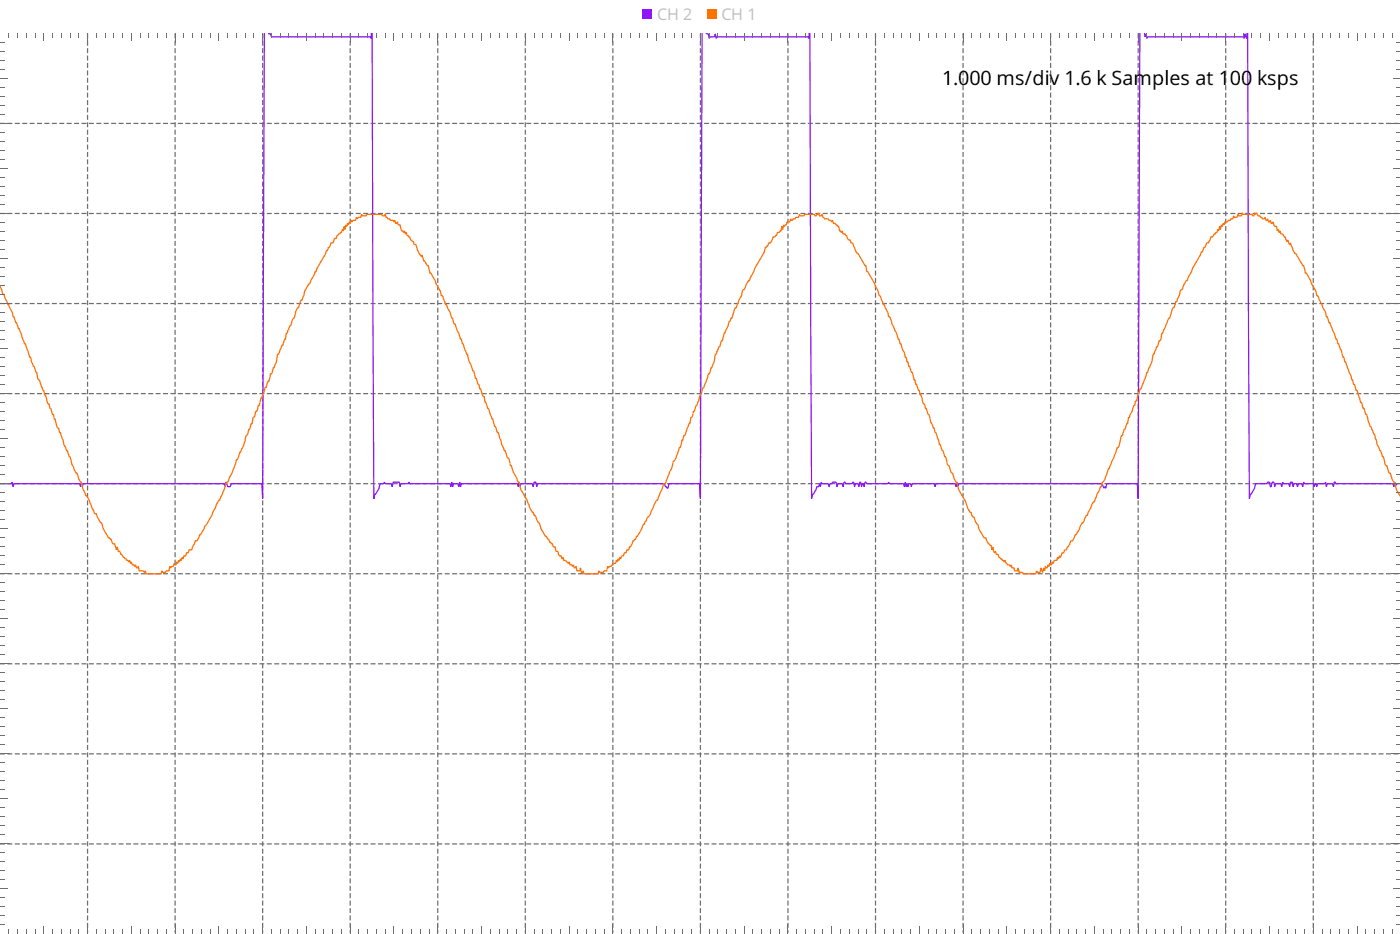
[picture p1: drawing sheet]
<svg xmlns="http://www.w3.org/2000/svg" width="300mm" height="200mm" viewBox="0 0 300 200" stroke-linecap="round" stroke-linejoin="round" font-family="sans-serif">
<defs><g id="words">
<g font-size="4.2">
<text x="201.8" y="18.2">1.000 ms/div 1.6 k Samples at 1</text>
<text x="263.4" y="18.2">00 ksps</text>
</g>
<g font-size="3.4" fill="#bebebe">
<text x="140.8" y="4.2">CH 2</text>
<text x="154.5" y="4.2">CH 1</text>
</g>
</g></defs>
<g fill="none" stroke="#6e6e6f" stroke-width=".26" stroke-dasharray="1.1 .5" stroke-linecap="butt">
<path d="M18.8 7.1v192.7M37.5 7.1v192.7M56.3 7.1v192.7M75 7.1v192.7M93.8 7.1v192.7M112.5 7.1v192.7M131.3 7.1v192.7M150 7.1v192.7M168.8 7.1v192.7M187.5 7.1v192.7M206.3 7.1v192.7M225 7.1v192.7"/>
<path d="M243.8 7.1v192.7M262.5 7.1v192.7M281.3 7.1v192.7M0 26.4h299.8M0 45.7h299.8M0 65h299.8M0 84.3h299.8M0 103.6h299.8M0 122.9h299.8M0 142.2h299.8M0 161.4h299.8M0 180.7h299.8"/>
</g>
<path d="M56.6 7.1l-.3 99.7-.2-3.2h-6.6l-.2 .6h-.5l-.4-.9-.2 .9-.2-.6h-30.2l-.2 .6-.2-.9-.1 .9-.2-.6h-14.1l-.2 .6-.2-.9-.2 .3h-2.4M57.5 7.1l.1 .2h.3l.2 .6h21.2l.2 .3 .1-1.1M79.7 7.1l.4 99.7 .2-1h.1l.8-1.2 .2-1h.7l.2-.3 .2 .3h1.3l.2 .6 .2-.9h1.3l.2 .9 .2-.6h1.5l.2-.3 .2 .3h8.6l.2 .6 .2-.9 .1 .9 .2-.6h1l.2 .6 .1-.9 .2 .9 .2-.6h12l.2 .6 .2-.9 .2 .9 .2-.6h2.4l.2 .6 .2-.9h.4l.2 .9 .1-.6h27.2l.2 .6h.2l.2 .4h.2l.2-1h6.5l.2 3.2 .4-99.7M151.3 7.1v.2h.4l.2 .9 .2-.3h.9l.2-.6 .2 .9 .2-.3h19.5l.2 .3v-1.1M173.5 7.1l.3 99.7 .2-1h.2l.8-1.6h.3l.2-.6 .2 .6 .2-.9 .2 .3h1.3l.2 .6 .2-.6h.3l.2-.3h.8l.2 .9 .2-.6h.9l.2 .6 .2-.9h.2l.1 .3h1.4l.1-.3h.2l.2 .9 .2-.6h.6l.2 .6 .1-.9h.2l.2 .9 .2-.6h.2l.2 .6 .2-.9h.2l.1 .3h4.5l.2-.3 .2 .3h3l.2 .6 .2-.9 .2 .9 .2-.6 .2 .6 .1-.6h.4l.2 .6 .2-.6h4.7l.2 .6 .2-.6h4.1l.2 .6 .2-.9 .2 .9 .1-.6h30.8l.4 1 .2-.4 .1 .4 .2-1h6.6l.2 3.2 .3-99.7M245.1 7.1l.2 .8 .2-.6 .2 .9 .1-.3h20.5l.2 .3 .2-.9 .3 .9 .1-1.1M267.2 7.1l.4 99.7 .2-1h.2l.7-1.2 .2-1h2.4l.2-.3h.4l.2 .9h.2l.2-.9h.3l.2 .9 .2-.6h1.1l.2 .6 .2-.9 .2 .3h1.1l.2 .6 .2-.9h.4l.2 .9 .2-.6h.5l.2 .6 .2-.6h.7l.2 .6 .2-.9 .2 .3h1.9l.2 .6 .2-.6h.1l.2 .6 .2-.6h1.5l.2-.3 .2 .9 .2-.6h1.1l.2 .6 .2-.9h.2l.2 .3h12.1l.2 .6 .2-.9 .2 .9 .2-.6h.7" fill="none" stroke="#9013fe" stroke-width=".26"/>
<path d="M0 61.4l.4 .6 .2 1h.2l.1 .3 .8 1.9h.2l.7 1.7 .2 .9h.2l.4 1.3h.2l.3 1.3h.2l.4 1 .8 2.2h.1l1.7 4.9h.2l.4 1.2h.2l.2 1.3 .2 .4h.1l.8 2.2h.2l.7 2.6 .2 .3h.2l.2 1h.2l.4 1.3h.1l.8 2.5 .2 .4h.2l.2 .9h.1l.8 2.6 .6 1.3h.1l.4 1.3h.2l.4 1.6 .4 .6a1.58 1.58 0 0 0 .7 1.3l.4 1.3 .4 .7h.1l.4 1.6 .6 1.3h.2l.5 .9 1.2 2.9h.3l.2 .7 .8 1.3h.2l.3 1.2 1.2 2 .5 .3 .4 1h.4l.3 1.3 .2-.7 .2 1h.4l.2 .6h.2l.3 .7 1 .6 .2 .3 .2-.3 .1 .7 .2-.4 .2 .7h.4l.2 .3 .2-.3 .2 .6h.1l.2-.3 .2 1h1l.1 .3 .2-.3 .2 .6h3.2l.2-.6 .2 .3h.5l.2-.3h.6l.2-1 .2 .3 .2-.3h.3l.2-.6 .2 .3h.2l.2-.7 .2 .4 .2-.7 .1 .3 .2-.6 .2 .3 .2-.6 .2 .3 .2-.7h.4l.1-.6h.4l.2-.6h.6l.7-2h.2a1.58 1.58 0 0 0 .8-1.3h.1l.8-1.3 .2-.6h.2l1.3-2.2 .9-2.3 .6-1h.2l1.3-3.5 .5-.7 .8-1.6 .7-1.9 .2-1h.2l.2-.3 .4-1.3h.2l.5-1.3 .6-2.2h.2l.2-.3 .2-1h.1l.4-1.3h.2l.2-1.3h.2l.4-1.3h.1l.2-.3 .8-2.6h.2l.7-2.2h.2l.4-1.3h.2l.3-1.6h.2l.2-.4 .2-.9h.2l.4-1 .3-1.9h.2l.2-.3 .6-1.7h.2l.3-1.2h.2l.2-1.3h.2l.6-1.6h.2l.3-1.3 .2-.4h.2l.4-1.6 .4-.6h.1l.4-1.3 .2-.3h.2l.6-2 .9-1.6h.2l1.1-2.5h.2l.2-.7 1.9-3.2 .1-.7h.2l.2-.6h.2l.2-.3 .2-.7h.4l.3-.9h.4l.2-.7 .9-.6 .2-.7 .2 .4 .2-1 .2 .6 .2-.9 .2 .3 .1-.7 .2 .4 .2-.7 .2 .3 .2-.6 .2 .3 .2-.3h.5l.2-.6 .2 .3 .2-.3h.6l.1-.7 .2 .3h.8l.2-.3h3.2l.1 .3h.4l.2-.3 .2 .7h.2l.2 .3h.3l.2 .3h.6l.2 .3 .2-.3 .2 .6h.1l.2-.3 .2 .7h.4l.4 1.3h.2l.1 .3 .2-.3 .2 .6 .2-.3 .2 .6 .6 .3 .1 .7 .6 .3 .2 .7h.4l.3 1.2 .4 .7 .4 .6 .2-.3 .4 1.3h.1l.6 1h.2l.4 1.6h.2l.1 .3 1.9 3.5 .2 1h.2l.2 .3 .5 1.6h.2l.8 1.7 .4 1.2h.1l.2 1 .2 .3h.2l1.1 3.3h.2l.2 .9h.2l.7 2.3h.2a4 4 0 0 0 .8 2.2l.4 1.3h.2l.3 1.6h.2l.4 1.3h.2l.2 1h.2l.3 1.3 .2 .3h.2l.2 1.3h.2l1.3 3.5h.2l.4 1.6h.1l.4 1.3h.2l.8 2.6 .5 1.3h.2l.4 1.3 .2 .3h.2l.3 1.6h.2l.4 1.3 .7 1.3 .2 .6 .2 .4h.2l.4 1.6 1.3 2.2 .6 1.6 .5 1h.2l.2 .7h.2l.2 .3a1.58 1.58 0 0 0 .7 1.3l.4 1.2 .9 1.7h.2l.4 .6h.2l.2 .6 .5 .4 .2 .6h.4l.2 1h.4l.3 .9h.4l.2 .7 .2-.3 .2 .6h.3l.6 .7 .2-.4 .2 .7h.4l.1 .3 .2-.3 .2 .6h.2l.2-.3 .2 1h.5l.2-.7 .2 1h.2l.2-.3 .2 .6h3l.2-.6 .2 .3h.7l.2-.3h.6l.1-1 .2 .3 .2-.3h.4l.6-.6h.3l.2-.7 .2 .3 .2-.6 .2 .3 .2-.6 .2 .3 .1-.7h.4l.2-.6h.4l.2-.6h.3l.2-.7h.2l.2-.3 .4-1 .5-.3 .2-.6h.2l.2-.4 .8-1.3 .1-.6 .2-.3h.2l.2-.7h.2l.4-.9a1.58 1.58 0 0 0 .7-1.3l1.1-2.3h.2l1.3-3.5h.4l1.3-3.2 .4-1.6h.2l.4-.7 .7-2.2h.2l.8-2.6h.1l.2-.3 .8-2.3h.2l.2-1.3h.1l.2-.3 .2-1h.2l.4-1.3h.2l1.3-3.8h.2l.7-2 .2-.9h.2l.2-.4 .2-.9h.2l.3-1 .4-1.9h.2l.6-1.6h.1l.4-1.3h.2l.4-1.6h.2l.5-1.3 .4-1.3h.2l.2-.7h.2l.5-1.9 .2-.3h.2l.6-1.6 .5-1 .2-1 .2-.3h.2l.9-1.9h.2l1.1-2.6 2.1-3.5 .2-1 .6-.3 .1-.7h.4l.6-1.3h.4l.1-.3h.2l.2-.6h.4l.2-.3h.2l.2-1 .1 .6 .2-.9 .2 .3 .2-.3h.2l.2-.7h.5l.2-.6 .2 .3h.2l.2-.3h.4l.2-.3h.5l.2-.7 .2 .3h.7l.2-.3h2.1l.2 .3h.2l.5-.6 .2 .6h.4l.2-.3 .2 .7h.2l.1 .3h.8l.2 .3h.4l.1 .3 .2-.3 .2 .6h.4l.6 .7h.1l.2 1h.2l.2 .3 .2-.3 .2 .6h.4l.1 .3h.2l.4 1h.4l.2 .6h.3l.4 1a2.74 2.74 0 0 0 1 1.6l1.3 2.3h.2l.1 1.3h.2l1.5 2.5 .8 1.6 .2 1h.2l.1 .3 .6 1.6h.2l.7 1.7 .2 .9h.2l.2 .3 1.7 4.6h.2l.2 .9h.2l.3 1.3 .4 .7 .2 .9h.2l.2 1h.2l.1 1h.2l.4 1.2h.2l.7 2.6h.2l.4 1.3h.2l.2 1h.2l.3 1.6 .2 .3h.2l.2 1h.2l.4 1.3h.2l.3 1.6 .6 1.3h.2l.2 .9h.2l.7 2.6h.2l.4 1.3h.2l.3 1.3h.2l.4 1.6 .2 .3h.2l.4 1.3 .1 .3h.2l.2 .7a1.58 1.58 0 0 0 .8 1.3 10.3 10.3 0 0 0 1.7 3.8l.5 1.6 .6 1h.2l.3 1h.2l.8 1.6h.2l.2 .9 1.1 2h.4a2.74 2.74 0 0 0 .9 1.6h.2l.2 1 .2-.7 .3 1.3 .2-.3 .2 .6h.4l.2 .7h.2l.9 .9 .2-.3 .2 .7h.2l.1 .3h.4l.2 .3 .2-.3 .2 .6h.4l.1 .7h.6l.2-.7 .2 1h.7l.2 .3h2.6l.2-.6 .2 .3h.6l.2-1 .3 1 .2-1 .2 .7 .2-1 .2 .3h.2l.2-.6 .2 .3 .1-.6 .2 .3h.2l.2-.7 .2 .4 .2-.7h.5l.2-.6 .2 .3 .2-.7 .2 .4 .4-1h.3l.2-.6h.4l.2-.7a1.58 1.58 0 0 0 .7-1.3h.4l.6-1.3h.2l.7-1.3a2.74 2.74 0 0 1 1-1.6 1.58 1.58 0 0 1 .7-1.2l.8-1.7a1.58 1.58 0 0 1 .7-1.2l.6-1.7 .7-1.6h.2l.2-.9h.2l.4-.7 .7-2.2h.2l.9-2.3 .8-2.2h.2l.2-.4 .5-2.2h.2l.4-1.3h.2l.3-1.3h.2l.2-1.3h.2l.6-1.3 .3-1.3h.2l.8-2.5h.2l.2-1h.1l.2-.3 1.2-3.3h.1l.2-.9h.2l.4-1 .4-1.9h.2l.5-1.6h.2l.4-1.3h.2l.2-.3 .1-1.3h.2l1.2-2.9 .1-.4h.2l.6-1.9 .2-.3h.2l.3-1.3h.2l.6-1.3 .2-1 .2-.3h.2l.9-1.9h.2l1.1-2.6 1.7-2.9 .2-.6h.2l.2-.4 .1-.6h.2l.4-1h.4l.5-1.3h.4l.4-.6 .6-.3 .1-.7 .2 .4 .2-1 .2 .6 .2-.9 .2 .3 .2-.7 .2 .4 .1-.7h.6l.2-.3h.4l.2-.3h.3l.2-.7 .2 .4h.6l.2-.7 .1 .3h.6l.2-.6 .2 .3h1.9l.1 .3h.2l.2-.6 .2 .3 .2-.3 .4 .6h.3l.6 .7h.4l.2-.3 .2 .6h.1l.2-.3 .2 .6h.2l.2-.3 .2 .6h.2l.2-.3 .3 1h.4l.2 1 .2-.4 .2 .7 .2-.3 .1 .6h.4l.4 .6h.2l.4 1 .1-.3 .4 1 .2-.4 .4 1a2.74 2.74 0 0 0 .9 1.6l1.3 2.3h.2l.4 1.6h.2l.9 1.6 .2 .6 .9 1.6 .2 1h.2l.2 .3 1.5 3.3 .2 .9h.2l.4 1.3h.1l1 2.3 .4 1.3h.1l.2 .9h.2l.4 1.3h.2l.4 1.6h.1l.2 1h.2l.4 1.3 .7 1.6 .2 1h.2l.2 .9h.2l.4 1.3h.2l.7 2.6h.2l.9 2.6h.2l.8 2.5h.2l.5 1.7h.2l.6 2.2 .5 1.3h.2l.4 1.3h.2l.4 1.6 .1 .3h.2l.4 1.3 .2 .3h.2l.2 .7a1.58 1.58 0 0 0 .7 1.3 6.4 6.4 0 0 0 1.1 2.9" fill="none" stroke="#ff7200" stroke-width=".26"/>
<g fill="#6e6e6f">
<path d="M1.9 7.1v1.1z"/>
<path d="M3.7 7.1l.1 1.1z"/>
<path d="M5.6 7.1v1.1z"/>
<path d="M7.5 7.1v1.1z"/>
<path d="M11.2 7.1l.1 1.1z"/>
<path d="M13.1 7.1v1.1z"/>
<path d="M15 7.1v1.1z"/>
<path d="M16.9 7.1v1.1z"/>
<path d="M20.6 7.1v1.1z"/>
<path d="M22.5 7.1v1.1z"/>
<path d="M24.4 7.1v1.1z"/>
<path d="M26.2 7.1l.1 1.1z"/>
<path d="M30 7.1v1.1z"/>
<path d="M31.9 7.1v1.1z"/>
<path d="M33.7 7.1l.1 1.1z"/>
<path d="M35.6 7.1v1.1z"/>
<path d="M39.4 7.1v1.1z"/>
<path d="M41.2 7.1l.1 1.1z"/>
<path d="M43.1 7.1v1.1z"/>
<path d="M45 7.1v1.1z"/>
<path d="M48.7 7.1l.1 1.1z"/>
<path d="M50.6 7.1v1.1z"/>
<path d="M52.5 7.1v1.1z"/>
<path d="M54.4 7.1v1.1z"/>
<path d="M58.1 7.1v1.1z"/>
<path d="M60 7.1v1.1z"/>
<path d="M61.9 7.1v1.1z"/>
<path d="M63.7 7.1l.1 1.1z"/>
<path d="M67.5 7.1v1.1z"/>
<path d="M69.4 7.1v1.1z"/>
<path d="M71.2 7.1l.1 1.1z"/>
<path d="M73.1 7.1v1.1z"/>
<path d="M76.9 7.1v1.1z"/>
<path d="M78.7 7.1l.1 1.1z"/>
<path d="M80.6 7.1l.1 1.1z"/>
<path d="M82.5 7.1v1.1z"/>
<path d="M86.2 7.1l.1 1.1z"/>
<path d="M88.1 7.1l.1 1.1z"/>
<path d="M90 7.1v1.1z"/>
<path d="M91.9 7.1v1.1z"/>
<path d="M95.6 7.1l.1 1.1z"/>
<path d="M97.5 7.1v1.1z"/>
<path d="M99.4 7.1v1.1z"/>
<path d="M101.2 7.1l.1 1.1z"/>
<path d="M105 7.1v1.1z"/>
<path d="M106.9 7.1v1.1z"/>
<path d="M108.7 7.1l.1 1.1z"/>
<path d="M110.6 7.1l.1 1.1z"/>
<path d="M114.4 7.1v1.1z"/>
<path d="M116.2 7.1l.1 1.1z"/>
<path d="M118.1 7.1l.1 1.1z"/>
<path d="M120 7.1v1.1z"/>
<path d="M123.8 7.1v1.1z"/>
<path d="M125.6 7.1l.1 1.1z"/>
<path d="M127.5 7.1v1.1z"/>
<path d="M129.4 7.1v1.1z"/>
<path d="M133.1 7.1l.1 1.1z"/>
<path d="M135 7.1v1.1z"/>
<path d="M136.9 7.1v1.1z"/>
<path d="M138.8 7.1v1.1z"/>
<path d="M142.5 7.1v1.1z"/>
<path d="M144.4 7.1v1.1z"/>
<path d="M146.3 7.1v1.1z"/>
<path d="M148.1 7.1l.1 1.1z"/>
<path d="M151.9 7.1v1.1z"/>
<path d="M153.8 7.1v1.1z"/>
<path d="M155.6 7.1l.1 1.1z"/>
<path d="M157.5 7.1v1.1z"/>
<path d="M161.3 7.1v1.1z"/>
<path d="M163.1 7.1l.1 1.1z"/>
<path d="M165 7.1v1.1z"/>
<path d="M166.9 7.1v1.1z"/>
<path d="M170.6 7.1l.1 1.1z"/>
<path d="M172.5 7.1v1.1z"/>
<path d="M174.4 7.1v1.1z"/>
<path d="M176.3 7.1v1.1z"/>
<path d="M180 7.1v1.1z"/>
<path d="M181.9 7.1v1.1z"/>
<path d="M183.8 7.1v1.1z"/>
<path d="M185.6 7.1l.1 1.1z"/>
<path d="M189.4 7.1v1.1z"/>
<path d="M191.3 7.1v1.1z"/>
<path d="M193.1 7.1l.1 1.1z"/>
<path d="M195 7.1v1.1z"/>
<path d="M198.8 7.1v1.1z"/>
<path d="M200.6 7.1l.1 1.1z"/>
<path d="M202.5 7.1v1.1z"/>
<path d="M204.4 7.1v1.1z"/>
<path d="M208.1 7.1l.1 1.1z"/>
<path d="M210 7.1v1.1z"/>
<path d="M211.9 7.1v1.1z"/>
<path d="M213.8 7.1v1.1z"/>
<path d="M217.5 7.1v1.1z"/>
<path d="M219.4 7.1v1.1z"/>
<path d="M221.3 7.1v1.1z"/>
<path d="M223.1 7.1l.1 1.1z"/>
<path d="M226.9 7.1v1.1z"/>
<path d="M228.8 7.1v1.1z"/>
<path d="M230.6 7.1l.1 1.1z"/>
<path d="M232.5 7.1v1.1z"/>
<path d="M236.3 7.1v1.1z"/>
<path d="M238.1 7.1l.1 1.1z"/>
<path d="M240 7.1v1.1z"/>
<path d="M241.9 7.1v1.1z"/>
<path d="M245.6 7.1l.1 1.1z"/>
<path d="M247.5 7.1v1.1z"/>
<path d="M249.4 7.1v1.1z"/>
<path d="M251.3 7.1v1.1z"/>
<path d="M255 7.1v1.1z"/>
<path d="M256.9 7.1v1.1z"/>
<path d="M258.8 7.1v1.1z"/>
<path d="M260.6 7.1l.1 1.1z"/>
<path d="M264.4 7.1v1.1z"/>
<path d="M266.3 7.1v1.1z"/>
<path d="M268.1 7.1l.1 1.1z"/>
<path d="M270 7.1v1.1z"/>
<path d="M273.8 7.1v1.1z"/>
<path d="M275.6 7.1l.1 1.1z"/>
<path d="M277.5 7.1v1.1z"/>
<path d="M279.4 7.1v1.1z"/>
<path d="M283.1 7.1l.1 1.1z"/>
<path d="M285 7.1l.1 1.1z"/>
<path d="M286.9 7.1v1.1z"/>
<path d="M288.8 7.1v1.1z"/>
<path d="M292.5 7.1l.1 1.1z"/>
<path d="M294.4 7.1v1.1z"/>
<path d="M296.3 7.1v1.1z"/>
<path d="M298.1 7.1l.1 1.1z"/>
<path d="M9.4 7.1v1.6z"/>
<path d="M28.1 7.1v1.6z"/>
<path d="M46.9 7.1v1.6z"/>
<path d="M65.6 7.1v1.6z"/>
<path d="M84.4 7.1v1.6z"/>
<path d="M103.1 7.1l.1 1.6z"/>
<path d="M121.9 7.1v1.6z"/>
<path d="M140.6 7.1l.1 1.6z"/>
<path d="M159.4 7.1v1.6z"/>
<path d="M178.1 7.1l.1 1.6z"/>
<path d="M196.9 7.1v1.6z"/>
<path d="M215.6 7.1l.1 1.6z"/>
<path d="M234.4 7.1v1.6z"/>
<path d="M253.1 7.1l.1 1.6z"/>
<path d="M271.9 7.1v1.6z"/>
<path d="M290.6 7.1l.1 1.6z"/>
</g>
<g fill="none" stroke="#6e6e6f" stroke-width=".21">
<path d="M18.8 7.1v2.2M37.5 7.1v2.2M56.3 7.1v2.2M75 7.1v2.2M93.8 7.1v2.2M112.5 7.1v2.2M131.3 7.1v2.2M150 7.1v2.2M168.8 7.1v2.2M187.5 7.1v2.2M206.3 7.1v2.2M225 7.1v2.2"/>
<path d="M243.8 7.1v2.2M262.5 7.1v2.2M281.3 7.1v2.2"/>
</g>
<g fill="#6e6e6f">
<path d="M1.9 199v1z"/>
<path d="M3.7 199l.1 1z"/>
<path d="M5.6 199v1z"/>
<path d="M7.5 199v1z"/>
<path d="M11.2 199l.1 1z"/>
<path d="M13.1 199v1z"/>
<path d="M15 199v1z"/>
<path d="M16.9 199v1z"/>
<path d="M20.6 199v1z"/>
<path d="M22.5 199v1z"/>
<path d="M24.4 199v1z"/>
<path d="M26.2 199l.1 1z"/>
<path d="M30 199v1z"/>
<path d="M31.9 199v1z"/>
<path d="M33.7 199l.1 1z"/>
<path d="M35.6 199v1z"/>
<path d="M39.4 199v1z"/>
<path d="M41.2 199l.1 1z"/>
<path d="M43.1 199v1z"/>
<path d="M45 199v1z"/>
<path d="M48.7 199l.1 1z"/>
<path d="M50.6 199v1z"/>
<path d="M52.5 199v1z"/>
<path d="M54.4 199v1z"/>
<path d="M58.1 199v1z"/>
<path d="M60 199v1z"/>
<path d="M61.9 199v1z"/>
<path d="M63.7 199l.1 1z"/>
<path d="M67.5 199v1z"/>
<path d="M69.4 199v1z"/>
<path d="M71.2 199l.1 1z"/>
<path d="M73.1 199v1z"/>
<path d="M76.9 199v1z"/>
<path d="M78.7 199l.1 1z"/>
<path d="M80.6 199l.1 1z"/>
<path d="M82.5 199v1z"/>
<path d="M86.2 199l.1 1z"/>
<path d="M88.1 199l.1 1z"/>
<path d="M90 199v1z"/>
<path d="M91.9 199v1z"/>
<path d="M95.6 199l.1 1z"/>
<path d="M97.5 199v1z"/>
<path d="M99.4 199v1z"/>
<path d="M101.2 199l.1 1z"/>
<path d="M105 199v1z"/>
<path d="M106.9 199v1z"/>
<path d="M108.7 199l.1 1z"/>
<path d="M110.6 199l.1 1z"/>
<path d="M114.4 199v1z"/>
<path d="M116.2 199l.1 1z"/>
<path d="M118.1 199l.1 1z"/>
<path d="M120 199v1z"/>
<path d="M123.8 199v1z"/>
<path d="M125.6 199l.1 1z"/>
<path d="M127.5 199v1z"/>
<path d="M129.4 199v1z"/>
<path d="M133.1 199l.1 1z"/>
<path d="M135 199v1z"/>
<path d="M136.9 199v1z"/>
<path d="M138.8 199v1z"/>
<path d="M142.5 199v1z"/>
<path d="M144.4 199v1z"/>
<path d="M146.3 199v1z"/>
<path d="M148.1 199l.1 1z"/>
<path d="M151.9 199v1z"/>
<path d="M153.8 199v1z"/>
<path d="M155.6 199l.1 1z"/>
<path d="M157.5 199v1z"/>
<path d="M161.3 199v1z"/>
<path d="M163.1 199l.1 1z"/>
<path d="M165 199v1z"/>
<path d="M166.9 199v1z"/>
<path d="M170.6 199l.1 1z"/>
<path d="M172.5 199v1z"/>
<path d="M174.4 199v1z"/>
<path d="M176.3 199v1z"/>
<path d="M180 199v1z"/>
<path d="M181.9 199v1z"/>
<path d="M183.8 199v1z"/>
<path d="M185.6 199l.1 1z"/>
<path d="M189.4 199v1z"/>
<path d="M191.3 199v1z"/>
<path d="M193.1 199l.1 1z"/>
<path d="M195 199v1z"/>
<path d="M198.8 199v1z"/>
<path d="M200.6 199l.1 1z"/>
<path d="M202.5 199v1z"/>
<path d="M204.4 199v1z"/>
<path d="M208.1 199l.1 1z"/>
<path d="M210 199v1z"/>
<path d="M211.9 199v1z"/>
<path d="M213.8 199v1z"/>
<path d="M217.5 199v1z"/>
<path d="M219.4 199v1z"/>
<path d="M221.3 199v1z"/>
<path d="M223.1 199l.1 1z"/>
<path d="M226.9 199v1z"/>
<path d="M228.8 199v1z"/>
<path d="M230.6 199l.1 1z"/>
<path d="M232.5 199v1z"/>
<path d="M236.3 199v1z"/>
<path d="M238.1 199l.1 1z"/>
<path d="M240 199v1z"/>
<path d="M241.9 199v1z"/>
<path d="M245.6 199l.1 1z"/>
<path d="M247.5 199v1z"/>
<path d="M249.4 199v1z"/>
<path d="M251.3 199v1z"/>
<path d="M255 199v1z"/>
<path d="M256.9 199v1z"/>
<path d="M258.8 199v1z"/>
<path d="M260.6 199l.1 1z"/>
<path d="M264.4 199v1z"/>
<path d="M266.3 199v1z"/>
<path d="M268.1 199l.1 1z"/>
<path d="M270 199v1z"/>
<path d="M273.8 199v1z"/>
<path d="M275.6 199l.1 1z"/>
<path d="M277.5 199v1z"/>
<path d="M279.4 199v1z"/>
<path d="M283.1 199l.1 1z"/>
<path d="M285 199l.1 1z"/>
<path d="M286.9 199v1z"/>
<path d="M288.8 199v1z"/>
<path d="M292.5 199l.1 1z"/>
<path d="M294.4 199v1z"/>
<path d="M296.3 199v1z"/>
<path d="M298.1 199l.1 1z"/>
<path d="M9.4 198.4v1.6z"/>
<path d="M28.1 198.4v1.6z"/>
<path d="M46.9 198.4v1.6z"/>
<path d="M65.6 198.4v1.6z"/>
<path d="M84.4 198.4v1.6z"/>
<path d="M103.1 198.4l.1 1.6z"/>
<path d="M121.9 198.4v1.6z"/>
<path d="M140.6 198.4l.1 1.6z"/>
<path d="M159.4 198.4v1.6z"/>
<path d="M178.1 198.4l.1 1.6z"/>
<path d="M196.9 198.4v1.6z"/>
<path d="M215.6 198.4l.1 1.6z"/>
<path d="M234.4 198.4v1.6z"/>
<path d="M253.1 198.4l.1 1.6z"/>
<path d="M271.9 198.4v1.6z"/>
<path d="M290.6 198.4l.1 1.6z"/>
</g>
<g fill="none" stroke="#6e6e6f" stroke-width=".21">
<path d="M18.8 197.9v2.1M37.5 197.9v2.1M56.3 197.9v2.1M75 197.9v2.1M93.8 197.9v2.1M112.5 197.9v2.1M131.3 197.9v2.1M150 197.9v2.1M168.8 197.9v2.1M187.5 197.9v2.1M206.3 197.9v2.1M225 197.9v2.1"/>
<path d="M243.8 197.9v2.1M262.5 197.9v2.1M281.3 197.9v2.1"/>
</g>
<g fill="#6e6e6f">
<path d="M299 198.1h.9z"/>
<path d="M299 196.2h.9z"/>
<path d="M299 194.2l.9 .1z"/>
<path d="M299 192.3h.9z"/>
<path d="M299 188.4l.9 .1z"/>
<path d="M299 186.5h.9z"/>
<path d="M299 184.6h.9z"/>
<path d="M299 182.7h.9z"/>
<path d="M299 178.8h.9z"/>
<path d="M299 176.9h.9z"/>
<path d="M299 174.9l.9 .1z"/>
<path d="M299 173h.9z"/>
<path d="M299 169.1l.9 .1z"/>
<path d="M299 167.2l.9 .1z"/>
<path d="M299 165.3h.9z"/>
<path d="M299 163.4h.9z"/>
<path d="M299 159.5h.9z"/>
<path d="M299 157.6h.9z"/>
<path d="M299 155.6l.9 .1z"/>
<path d="M299 153.7h.9z"/>
<path d="M299 149.9h.9z"/>
<path d="M299 147.9l.9 .1z"/>
<path d="M299 146h.9z"/>
<path d="M299 144.1h.9z"/>
<path d="M299 140.2h.9z"/>
<path d="M299 138.3h.9z"/>
<path d="M299 136.4h.9z"/>
<path d="M299 134.4l.9 .1z"/>
<path d="M299 130.6h.9z"/>
<path d="M299 128.6l.9 .1z"/>
<path d="M299 126.7h.9z"/>
<path d="M299 124.8h.9z"/>
<path d="M299 120.9l.9 .1z"/>
<path d="M299 119h.9z"/>
<path d="M299 117.1h.9z"/>
<path d="M299 115.1l.9 .1z"/>
<path d="M299 111.3h.9z"/>
<path d="M299 109.4h.9z"/>
<path d="M299 107.4l.9 .1z"/>
<path d="M299 105.5h.9z"/>
<path d="M299 101.6l.9 .1z"/>
<path d="M299 99.7h.9z"/>
<path d="M299 97.8h.9z"/>
<path d="M299 95.9h.9z"/>
<path d="M299 92h.9z"/>
<path d="M299 90.1h.9z"/>
<path d="M299 88.1l.9 .1z"/>
<path d="M299 86.2h.9z"/>
<path d="M299 82.4h.9z"/>
<path d="M299 80.4l.9 .1z"/>
<path d="M299 78.5h.9z"/>
<path d="M299 76.6h.9z"/>
<path d="M299 72.7h.9z"/>
<path d="M299 70.8h.9z"/>
<path d="M299 68.9h.9z"/>
<path d="M299 66.9l.9 .1z"/>
<path d="M299 63.1h.9z"/>
<path d="M299 61.1l.9 .1z"/>
<path d="M299 59.2h.9z"/>
<path d="M299 57.3h.9z"/>
<path d="M299 53.4l.9 .1z"/>
<path d="M299 51.5h.9z"/>
<path d="M299 49.6h.9z"/>
<path d="M299 47.6l.9 .1z"/>
<path d="M299 43.8h.9z"/>
<path d="M299 41.8l.9 .1z"/>
<path d="M299 39.9h.9z"/>
<path d="M299 38h.9z"/>
<path d="M299 34.1l.9 .1z"/>
<path d="M299 32.2h.9z"/>
<path d="M299 30.3h.9z"/>
<path d="M299 28.3l.9 .1z"/>
<path d="M299 24.5h.9z"/>
<path d="M299 22.6h.9z"/>
<path d="M299 20.6l.9 .1z"/>
<path d="M299 18.7h.9z"/>
<path d="M299 14.8l.9 .1z"/>
<path d="M299 12.9h.9z"/>
<path d="M299 11h.9z"/>
<path d="M299 9.1h.9z"/>
<path d="M298.5 190.4h1.4z"/>
<path d="M298.5 171.1h1.4z"/>
<path d="M298.5 151.8h1.4z"/>
<path d="M298.5 132.5h1.4z"/>
<path d="M298.5 113.2h1.4z"/>
<path d="M298.5 93.9l1.4 .1z"/>
<path d="M298.5 74.6l1.4 .1z"/>
<path d="M298.5 55.3l1.4 .1z"/>
<path d="M298.5 36.1h1.4z"/>
<path d="M298.5 16.8h1.4z"/>
<path d="M297.9 180.7l2 .1z"/>
<path d="M297.9 161.4l2 .1z"/>
<path d="M297.9 142.1l2 .1z"/>
<path d="M297.9 122.9h2z"/>
<path d="M297.9 103.6h2z"/>
<path d="M297.9 84.3h2z"/>
<path d="M297.9 65h2z"/>
<path d="M297.9 45.7h2z"/>
<path d="M297.9 26.4h2z"/>
<path d="M0 198.1h1.1z"/>
<path d="M0 196.2h1.1z"/>
<path d="M0 194.2l1.1 .1z"/>
<path d="M0 192.3h1.1z"/>
<path d="M0 188.4l1.1 .1z"/>
<path d="M0 186.5h1.1z"/>
<path d="M0 184.6h1.1z"/>
<path d="M0 182.7h1.1z"/>
<path d="M0 178.8h1.1z"/>
<path d="M0 176.9h1.1z"/>
<path d="M0 174.9l1.1 .1z"/>
<path d="M0 173h1.1z"/>
<path d="M0 169.1l1.1 .1z"/>
<path d="M0 167.2l1.1 .1z"/>
<path d="M0 165.3h1.1z"/>
<path d="M0 163.4h1.1z"/>
<path d="M0 159.5h1.1z"/>
<path d="M0 157.6h1.1z"/>
<path d="M0 155.6l1.1 .1z"/>
<path d="M0 153.7h1.1z"/>
<path d="M0 149.9h1.1z"/>
<path d="M0 147.9l1.1 .1z"/>
<path d="M0 146h1.1z"/>
<path d="M0 144.1h1.1z"/>
<path d="M0 140.2h1.1z"/>
<path d="M0 138.3h1.1z"/>
<path d="M0 136.4h1.1z"/>
<path d="M0 134.4l1.1 .1z"/>
<path d="M0 130.6h1.1z"/>
<path d="M0 128.6l1.1 .1z"/>
<path d="M0 126.7h1.1z"/>
<path d="M0 124.8h1.1z"/>
<path d="M0 120.9l1.1 .1z"/>
<path d="M0 119h1.1z"/>
<path d="M0 117.1h1.1z"/>
<path d="M0 115.1l1.1 .1z"/>
<path d="M0 111.3h1.1z"/>
<path d="M0 109.4h1.1z"/>
<path d="M0 107.4l1.1 .1z"/>
<path d="M0 105.5h1.1z"/>
<path d="M0 101.6l1.1 .1z"/>
<path d="M0 99.7h1.1z"/>
<path d="M0 97.8h1.1z"/>
<path d="M0 95.9h1.1z"/>
<path d="M0 92h1.1z"/>
<path d="M0 90.1h1.1z"/>
<path d="M0 88.1l1.1 .1z"/>
<path d="M0 86.2h1.1z"/>
<path d="M0 82.4h1.1z"/>
<path d="M0 80.4l1.1 .1z"/>
<path d="M0 78.5h1.1z"/>
<path d="M0 76.6h1.1z"/>
<path d="M0 72.7h1.1z"/>
<path d="M0 70.8h1.1z"/>
<path d="M0 68.9h1.1z"/>
<path d="M0 66.9l1.1 .1z"/>
<path d="M0 63.1h1.1z"/>
<path d="M0 61.1l1.1 .1z"/>
<path d="M0 59.2h1.1z"/>
<path d="M0 57.3h1.1z"/>
<path d="M0 53.4l1.1 .1z"/>
<path d="M0 51.5h1.1z"/>
<path d="M0 49.6h1.1z"/>
<path d="M0 47.6l1.1 .1z"/>
<path d="M0 43.8h1.1z"/>
<path d="M0 41.8l1.1 .1z"/>
<path d="M0 39.9h1.1z"/>
<path d="M0 38h1.1z"/>
<path d="M0 34.1l1.1 .1z"/>
<path d="M0 32.2h1.1z"/>
<path d="M0 30.3h1.1z"/>
<path d="M0 28.3l1.1 .1z"/>
<path d="M0 24.5h1.1z"/>
<path d="M0 22.6h1.1z"/>
<path d="M0 20.6l1.1 .1z"/>
<path d="M0 18.7h1.1z"/>
<path d="M0 14.8l1.1 .1z"/>
<path d="M0 12.9h1.1z"/>
<path d="M0 11h1.1z"/>
<path d="M0 9.1h1.1z"/>
<path d="M0 190.4h1.6z"/>
<path d="M0 171.1h1.6z"/>
<path d="M0 151.8h1.6z"/>
<path d="M0 132.5h1.6z"/>
<path d="M0 113.2h1.6z"/>
<path d="M0 93.9l1.6 .1z"/>
<path d="M0 74.6l1.6 .1z"/>
<path d="M0 55.3l1.6 .1z"/>
<path d="M0 36.1h1.6z"/>
<path d="M0 16.8h1.6z"/>
</g>
<path d="M0 26.4h2.1M0 45.7h2.1M0 65h2.1M0 84.3h2.1M0 103.6h2.1M0 122.9h2.1M0 142.2h2.1M0 161.4h2.1M0 180.7h2.1" fill="none" stroke="#6e6e6f" stroke-width=".21"/>
<path d="M137.6 1.9h2.1v2.1h-2.1z" fill-rule="evenodd" fill="#9013fe"/>
<path d="M151.3 1.9h2.2v2.1h-2.2z" fill-rule="evenodd" fill="#ff7200"/>
<use href="#words"/>
</svg>
